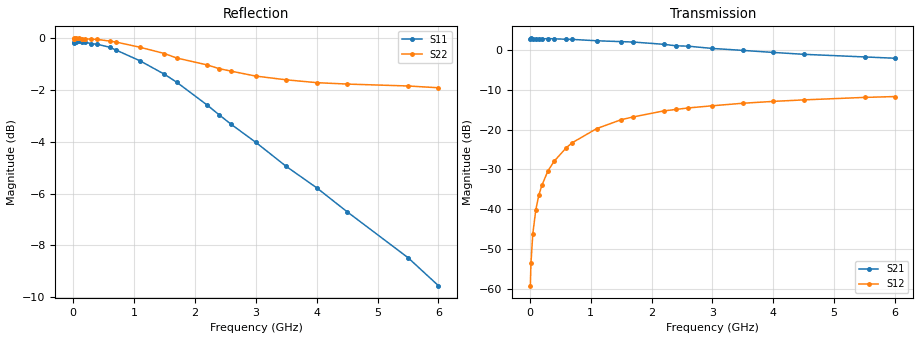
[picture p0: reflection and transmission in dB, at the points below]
! SIEMENS Discrete & RF Semiconductors
! BFY180
! Si NPN RF Bipolar Junction Transistor in MICRO-X
! VCE = 1.75 V  IC = 0.4 mA
! Common Emitter S-Parameters:  May  1997
# GHz  S  MA  R  50
!  f  S11  S21  S12  S22
! GHz  MAG  ANG  MAG  ANG  MAG  ANG  MAG  ANG
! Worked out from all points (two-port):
!   36 points, 10 MHz to 6 GHz, reference 50 ohm
!   highest |S21| = 2.86 dB at 20 MHz (marker M1); lowest = -2.1 dB at 6 GHz (marker M2)
!   |S21| within 3 dB of the highest: start of sweep to 3.482 GHz
!   lowest |S11| = -9.6 dB at 6 GHz (marker M3), VSWR 2.00, Z = 28.4 - j15.5 ohm
!   |S11| at or under -10 dB: nowhere
!   |S22| runs from -1.9 to 0.0 dB; largest |S21 - S12| = 1.4
!   S11 on the Smith chart (normalised r, x): 10 MHz: open; 700 MHz: 0.70, -5.05; 1.5 GHz: 0.53, -2.32; 2.4 GHz: 0.51, -1.36; 4 GHz: 0.52, -0.72; 6 GHz: 0.57, -0.31
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0.01  0.9843 -0.2  1.365 179.9  0.0011 94.3  0.998 -0.2
0.02  0.9772 -0.5  1.39 179.3  0.0021 96.6  0.9994 -0.4
0.05  0.983 -1.3  1.382 178.2  0.0049 85.6  0.9994 -1.1
0.1  0.9879 -3.1  1.378 176.2  0.0099 89.5  0.9996 -2.3
0.15  0.9836 -5.0  1.383 174.1  0.0151 86.6  0.9984 -3.4
0.2  0.9826 -6.2  1.37 171.8  0.02 85.1  0.9972 -4.4
0.3  0.9759 -9.5  1.38 167.8  0.0304 82.5  0.9962 -6.6
0.4  0.9735 -12.5  1.373 163.7  0.0399 80.6  0.995 -8.8
0.6  0.961 -18.8  1.355 154.9  0.0591 74.8  0.9876 -13.3
0.7  0.9496 -22.0  1.349 151.8  0.0684 72.6  0.9837 -15.4
1.1  0.9045 -33.4  1.297 136.6  0.1027 62.9  0.9608 -23.9
1.5  0.8522 -44.9  1.265 122.0  0.1326 53.8  0.9345 -31.9
1.7  0.8227 -51.2  1.25 115.0  0.1439 50.0  0.916 -35.7
2.2  0.7434 -63.3  1.171 97.6  0.171 40.6  0.8884 -44.4
2.4  0.7113 -67.9  1.122 91.5  0.1786 37.6  0.8735 -47.5
2.6  0.6815 -72.4  1.109 85.4  0.1863 34.6  0.8638 -50.6
3  0.6296 -80.7  1.039 74.6  0.1985 28.8  0.8452 -56.5
3.5  0.5656 -89.2  0.982 61.7  0.2134 23.1  0.8313 -63.2
4  0.5143 -98.1  0.926 50.3  0.2252 17.3  0.8209 -70.0
4.5  0.4623 -106.1  0.877 39.8  0.2353 12.2  0.8157 -76.9
5.5  0.3769 -123.3  0.813 20.5  0.2527 2.3  0.8088 -90.9
6  0.3327 -133.2  0.783 11.8  0.259 -2.8  0.8024 -98.0
